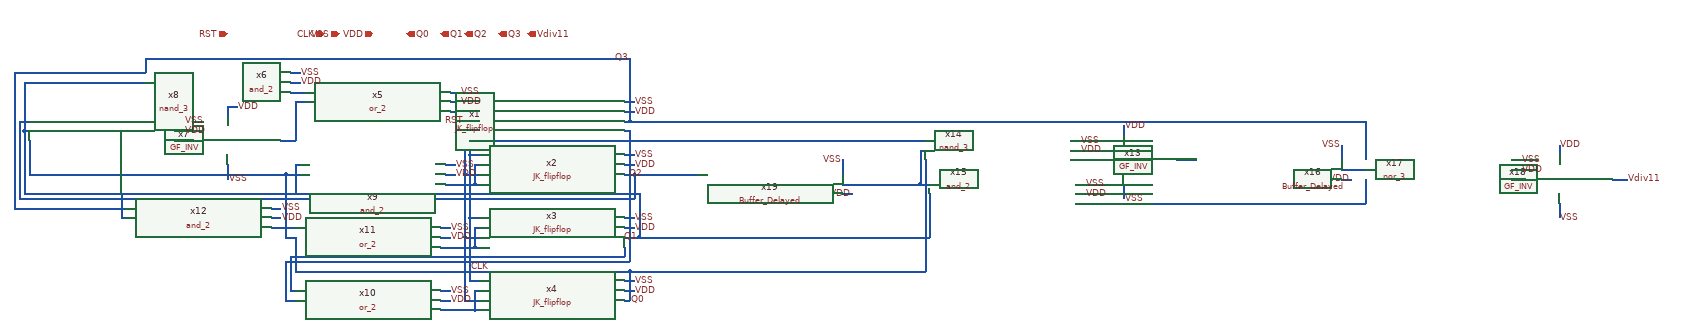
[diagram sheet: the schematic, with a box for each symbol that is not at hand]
v {xschem version=3.1.0 file_version=1.2
}
G {}
K {}
V {}
S {}
E {}
N 280 -50 300 -50 {
lab=VSS}
N 280 -30 300 -30 {
lab=VDD}
N -30 -30 -20 -30 {
lab=#net1}
N -30 -30 -30 10 {
lab=#net1}
N -30 10 -20 10 {
lab=#net1}
N 280 60 300 60 {
lab=VSS}
N 280 80 300 80 {
lab=VDD}
N -30 80 -20 80 {
lab=#net2}
N -30 80 -30 120 {
lab=#net2}
N -30 120 -20 120 {
lab=#net2}
N 280 190 300 190 {
lab=VSS}
N 280 210 300 210 {
lab=VDD}
N -30 210 -20 210 {
lab=#net3}
N -30 210 -30 250 {
lab=#net3}
N -30 250 -20 250 {
lab=#net3}
N 280 320 300 320 {
lab=VSS}
N 280 340 300 340 {
lab=VDD}
N -30 340 -20 340 {
lab=#net4}
N -30 340 -30 380 {
lab=#net4}
N -30 380 -20 380 {
lab=#net4}
N -40 -50 -20 -50 {
lab=CLK}
N -40 -50 -40 60 {
lab=CLK}
N -40 60 -20 60 {
lab=CLK}
N -40 60 -40 190 {
lab=CLK}
N -40 190 -20 190 {
lab=CLK}
N -40 190 -40 320 {
lab=CLK}
N -40 320 -20 320 {
lab=CLK}
N -50 -10 -20 -10 {
lab=RST}
N -50 -10 -50 100 {
lab=RST}
N -50 100 -20 100 {
lab=RST}
N -50 100 -50 230 {
lab=RST}
N -50 230 -20 230 {
lab=RST}
N -50 230 -50 360 {
lab=RST}
N -50 360 -20 360 {
lab=RST}
N -80 -30 -30 -30 {
lab=#net1}
N -410 -70 -380 -70 {
lab=#net5}
N -540 -40 -540 -20 {
lab=VDD}
N -540 80 -540 110 {
lab=VSS}
N -400 -50 -380 -50 {
lab=#net6}
N -400 -50 -400 30 {
lab=#net6}
N -430 30 -400 30 {
lab=#net6}
N -650 30 -610 30 {
lab=#net7}
N -90 120 -30 120 {
lab=#net2}
N -100 380 -30 380 {
lab=#net4}
N -100 250 -30 250 {
lab=#net3}
N -450 210 -410 210 {
lab=#net8}
N 280 360 290 360 {
lab=Q0}
N 290 300 290 360 {
lab=Q0}
N -400 300 290 300 {
lab=Q0}
N -400 230 -400 300 {
lab=Q0}
N 280 250 280 270 {
lab=#net9}
N -410 270 280 270 {
lab=#net9}
N -410 270 -410 340 {
lab=#net9}
N -410 340 -400 340 {
lab=#net9}
N 280 10 290 10 {
lab=#net10}
N 290 10 290 280 {
lab=#net10}
N -420 280 290 280 {
lab=#net10}
N -420 280 -420 360 {
lab=#net10}
N -420 360 -400 360 {
lab=#net10}
N 280 -10 290 -10 {
lab=Q3}
N 290 -140 290 -10 {
lab=Q3}
N -710 -140 290 -140 {
lab=Q3}
N -710 -140 -710 -110 {
lab=Q3}
N -980 -110 -710 -110 {
lab=Q3}
N -980 -110 -980 170 {
lab=Q3}
N -980 170 -750 170 {
lab=Q3}
N 280 230 310 230 {
lab=Q1}
N 310 140 310 230 {
lab=Q1}
N -960 140 310 140 {
lab=Q1}
N -960 30 -960 140 {
lab=Q1}
N -960 10 -960 30 {
lab=Q1}
N -960 10 -950 10 {
lab=Q1}
N -760 190 -750 190 {
lab=Q1}
N -760 140 -760 190 {
lab=Q1}
N -410 230 -400 230 {
lab=Q0}
N -420 230 -410 230 {
lab=Q0}
N -420 100 -420 230 {
lab=Q0}
N -420 100 -390 100 {
lab=Q0}
N -410 210 -400 210 {
lab=#net8}
N -400 80 -390 80 {
lab=Q1}
N -400 80 -400 140 {
lab=Q1}
N -950 30 -950 100 {
lab=Q0}
N -950 100 -420 100 {
lab=Q0}
N -960 -90 -960 10 {
lab=Q1}
N -960 -90 -710 -90 {
lab=Q1}
N 1310 0 1310 20 {
lab=VDD}
N 1310 120 1310 150 {
lab=VSS}
N 1200 70 1240 70 {
lab=#net11}
N 890 50 890 70 {
lab=Q2}
N 890 50 900 50 {
lab=Q2}
N 900 70 900 140 {
lab=Q0}
N 880 30 900 30 {
lab=CLK}
N -40 30 360 30 {
lab=CLK}
N 280 100 300 100 {
lab=Q2}
N 300 100 300 150 {
lab=Q2}
N -970 150 300 150 {
lab=Q2}
N -970 -10 -970 150 {
lab=Q2}
N -970 -10 -950 -10 {
lab=Q2}
N 300 100 370 100 {
lab=Q2}
N 890 70 890 100 {
lab=Q2}
N 290 300 380 300 {
lab=Q0}
N 890 100 890 120 {
lab=Q2}
N 890 120 910 120 {
lab=Q2}
N 310 230 390 230 {
lab=Q1}
N 290 -10 1070 -10 {
lab=Q3}
N 1810 10 1810 70 {
lab=Q3}
N 1210 160 1590 160 {
lab=#net12}
N 1420 70 1460 70 {
lab=#net13}
N 1760 110 1780 110 {
lab=VDD}
N 1760 40 1760 70 {
lab=VSS}
N 2210 40 2210 60 {
lab=VDD}
N 2210 160 2210 190 {
lab=VSS}
N 2110 110 2140 110 {
lab=#net14}
N -410 -110 -390 -110 {
lab=VSS}
N -410 -90 -390 -90 {
lab=VDD}
N -80 -70 -60 -70 {
lab=VSS}
N -80 -50 -60 -50 {
lab=VDD}
N -650 -10 -630 -10 {
lab=VSS}
N -650 10 -630 10 {
lab=VDD}
N -450 170 -430 170 {
lab=VSS}
N -450 190 -430 190 {
lab=VDD}
N -100 210 -80 210 {
lab=VSS}
N -100 230 -80 230 {
lab=VDD}
N -100 340 -80 340 {
lab=VSS}
N -100 360 -80 360 {
lab=VDD}
N -90 80 -70 80 {
lab=VSS}
N -90 100 -70 100 {
lab=VDD}
N 1200 30 1220 30 {
lab=VSS}
N 1200 50 1220 50 {
lab=VDD}
N 1210 120 1230 120 {
lab=VSS}
N 1210 140 1230 140 {
lab=VDD}
N 2110 70 2130 70 {
lab=VSS}
N 2110 90 2130 90 {
lab=VDD}
N -540 -40 -520 -40 {
lab=VDD}
N 2320 110 2350 110 {
lab=Vdiv11}
N 1590 -10 1810 -10 {
lab=Q3}
N 1590 160 1810 160 {
lab=#net12}
N 1760 90 1810 90 {
lab=#net15}
N 1810 110 1810 160 {
lab=#net12}
N 1810 -10 1810 10 {
lab=Q3}
N 1070 -10 1590 -10 {
lab=Q3}
N 360 30 880 30 {
lab=CLK}
N 390 230 910 230 {
lab=Q1}
N 910 140 910 230 {
lab=Q1}
N 900 140 900 300 {
lab=Q0}
N 380 300 900 300 {
lab=Q0}
N 730 140 750 140 {
lab=VDD}
N 730 70 730 100 {
lab=VSS}
N 370 100 430 100 {}
N 730 120 890 120 {}
C {JK_flipflop.sym} 130 -20 0 0 {name=x1}
C {devices/lab_pin.sym} 300 -50 2 0 {name=p10 sig_type=std_logic lab=VSS}
C {devices/lab_pin.sym} 300 -30 2 0 {name=p11 sig_type=std_logic lab=VDD}
C {JK_flipflop.sym} 130 90 0 0 {name=x2}
C {devices/lab_pin.sym} 300 60 2 0 {name=p1 sig_type=std_logic lab=VSS}
C {devices/lab_pin.sym} 300 80 2 0 {name=p2 sig_type=std_logic lab=VDD}
C {JK_flipflop.sym} 130 220 0 0 {name=x3}
C {devices/lab_pin.sym} 300 190 2 0 {name=p3 sig_type=std_logic lab=VSS}
C {devices/lab_pin.sym} 300 210 2 0 {name=p4 sig_type=std_logic lab=VDD}
C {JK_flipflop.sym} 130 350 0 0 {name=x4}
C {devices/lab_pin.sym} 300 320 2 0 {name=p5 sig_type=std_logic lab=VSS}
C {devices/lab_pin.sym} 300 340 2 0 {name=p6 sig_type=std_logic lab=VDD}
C {or_2.sym} -230 -50 0 0 {name=x5}
C {GF_INV.sym} -540 30 0 0 {name=x7}
C {nand_3.sym} -800 10 0 0 {name=x8}
C {or_2.sym} -250 360 0 0 {name=x10}
C {or_2.sym} -250 230 0 0 {name=x11}
C {GF_INV.sym} 1310 70 0 0 {name=x13}
C {nand_3.sym} 1050 50 0 0 {name=x14}
C {nor_3.sym} 1960 90 0 0 {name=x17}
C {GF_INV.sym} 2210 110 0 0 {name=x18}
C {devices/ipin.sym} -340 -190 0 0 {name=p9 lab=CLK}
C {devices/iopin.sym} -310 -190 0 0 {name=p12 lab=VSS
}
C {devices/iopin.sym} -240 -190 0 0 {name=p13 lab=VDD}
C {devices/opin.sym} -170 -190 0 0 {name=p14 lab=Q0}
C {devices/opin.sym} -100 -190 0 0 {name=p27 lab=Q1}
C {devices/ipin.sym} -540 -190 0 0 {name=p30 lab=RST}
C {devices/opin.sym} 80 -190 0 0 {name=p18 lab=Vdiv11}
C {devices/opin.sym} -50 -190 0 0 {name=p16 lab=Q2}
C {devices/opin.sym} 20 -190 0 0 {name=p17 lab=Q3}
C {devices/lab_pin.sym} -390 -110 2 0 {name=p7 sig_type=std_logic lab=VSS}
C {devices/lab_pin.sym} -390 -90 2 0 {name=p8 sig_type=std_logic lab=VDD}
C {devices/lab_pin.sym} -60 -70 2 0 {name=p15 sig_type=std_logic lab=VSS}
C {devices/lab_pin.sym} -60 -50 2 0 {name=p19 sig_type=std_logic lab=VDD}
C {devices/lab_pin.sym} -630 -10 2 0 {name=p20 sig_type=std_logic lab=VSS}
C {devices/lab_pin.sym} -630 10 2 0 {name=p21 sig_type=std_logic lab=VDD}
C {devices/lab_pin.sym} -430 170 2 0 {name=p22 sig_type=std_logic lab=VSS}
C {devices/lab_pin.sym} -430 190 2 0 {name=p23 sig_type=std_logic lab=VDD}
C {devices/lab_pin.sym} -80 210 2 0 {name=p24 sig_type=std_logic lab=VSS}
C {devices/lab_pin.sym} -80 230 2 0 {name=p25 sig_type=std_logic lab=VDD}
C {devices/lab_pin.sym} -80 340 2 0 {name=p26 sig_type=std_logic lab=VSS}
C {devices/lab_pin.sym} -80 360 2 0 {name=p28 sig_type=std_logic lab=VDD}
C {devices/lab_pin.sym} -70 80 2 0 {name=p29 sig_type=std_logic lab=VSS}
C {devices/lab_pin.sym} -70 100 2 0 {name=p31 sig_type=std_logic lab=VDD}
C {devices/lab_pin.sym} 1220 30 2 0 {name=p32 sig_type=std_logic lab=VSS}
C {devices/lab_pin.sym} 1220 50 2 0 {name=p33 sig_type=std_logic lab=VDD}
C {devices/lab_pin.sym} 1230 120 2 0 {name=p34 sig_type=std_logic lab=VSS}
C {devices/lab_pin.sym} 1230 140 2 0 {name=p35 sig_type=std_logic lab=VDD}
C {devices/lab_pin.sym} 2130 70 2 0 {name=p36 sig_type=std_logic lab=VSS}
C {devices/lab_pin.sym} 2130 90 2 0 {name=p37 sig_type=std_logic lab=VDD}
C {devices/lab_pin.sym} -540 110 2 0 {name=p38 sig_type=std_logic lab=VSS}
C {devices/lab_pin.sym} -520 -40 2 0 {name=p39 sig_type=std_logic lab=VDD}
C {devices/lab_pin.sym} 1310 150 2 0 {name=p40 sig_type=std_logic lab=VSS}
C {devices/lab_pin.sym} 1310 0 2 0 {name=p41 sig_type=std_logic lab=VDD}
C {devices/lab_pin.sym} 1760 40 0 0 {name=p42 sig_type=std_logic lab=VSS}
C {devices/lab_pin.sym} 2210 190 2 0 {name=p43 sig_type=std_logic lab=VSS}
C {devices/lab_pin.sym} 1780 110 3 0 {name=p44 sig_type=std_logic lab=VDD}
C {devices/lab_pin.sym} 2210 40 2 0 {name=p45 sig_type=std_logic lab=VDD}
C {devices/lab_pin.sym} 290 -140 1 0 {name=p46 sig_type=std_logic lab=Q3}
C {devices/lab_pin.sym} 320 100 3 0 {name=p47 sig_type=std_logic lab=Q2}
C {devices/lab_pin.sym} 310 230 3 0 {name=p48 sig_type=std_logic lab=Q1}
C {devices/lab_pin.sym} 290 360 2 0 {name=p49 sig_type=std_logic lab=Q0}
C {devices/lab_pin.sym} -40 290 2 0 {name=p50 sig_type=std_logic lab=CLK}
C {devices/lab_pin.sym} -50 -10 0 0 {name=p51 sig_type=std_logic lab=RST}
C {devices/lab_pin.sym} 2350 110 2 0 {name=p52 sig_type=std_logic lab=Vdiv11}
C {and_2.sym} -560 -90 0 0 {name=x6}
C {and_2.sym} -600 190 0 0 {name=x12}
C {and_2.sym} 1060 140 0 0 {name=x15}
C {and_2.sym} -240 100 0 0 {name=x9}
C {Buffer_Delayed.sym} 1610 90 0 0 {name=x16}
C {devices/lab_pin.sym} 730 70 0 0 {name=p53 sig_type=std_logic lab=VSS}
C {devices/lab_pin.sym} 750 140 3 0 {name=p54 sig_type=std_logic lab=VDD}
C {Buffer_Delayed.sym} 580 120 0 0 {name=x19}
